VERSION 5.7 ;
BUSBITCHARS "[]" ;
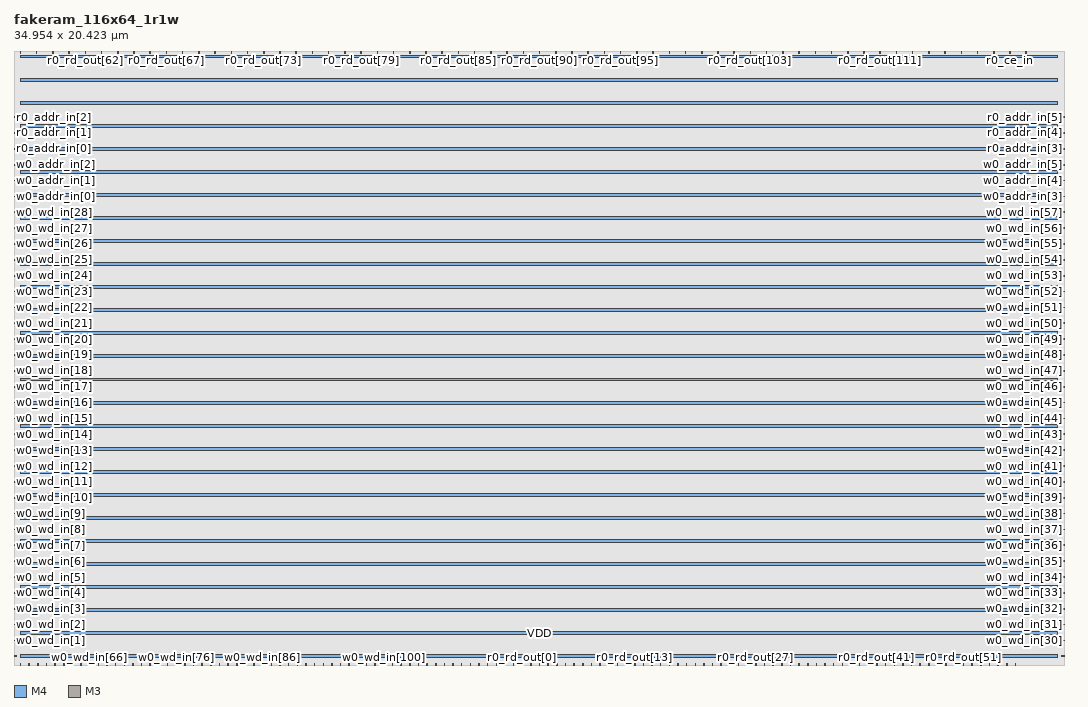
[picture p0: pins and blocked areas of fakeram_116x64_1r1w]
MACRO fakeram_116x64_1r1w
  FOREIGN fakeram_116x64_1r1w 0 0 ;
  SYMMETRY X Y R90 ;
  SIZE 34.954 BY 20.423 ;
  CLASS BLOCK ;
  PIN w0_wd_in[0]
    DIRECTION INPUT ;
    USE SIGNAL ;
    SHAPE ABUTMENT ;
    PORT
      LAYER M4 ;
      RECT 0.000 0.276 0.072 0.300 ;
    END
  END w0_wd_in[0]
  PIN w0_wd_in[1]
    DIRECTION INPUT ;
    USE SIGNAL ;
    SHAPE ABUTMENT ;
    PORT
      LAYER M4 ;
      RECT 0.000 0.804 0.072 0.828 ;
    END
  END w0_wd_in[1]
  PIN w0_wd_in[2]
    DIRECTION INPUT ;
    USE SIGNAL ;
    SHAPE ABUTMENT ;
    PORT
      LAYER M4 ;
      RECT 0.000 1.332 0.072 1.356 ;
    END
  END w0_wd_in[2]
  PIN w0_wd_in[3]
    DIRECTION INPUT ;
    USE SIGNAL ;
    SHAPE ABUTMENT ;
    PORT
      LAYER M4 ;
      RECT 0.000 1.860 0.072 1.884 ;
    END
  END w0_wd_in[3]
  PIN w0_wd_in[4]
    DIRECTION INPUT ;
    USE SIGNAL ;
    SHAPE ABUTMENT ;
    PORT
      LAYER M4 ;
      RECT 0.000 2.388 0.072 2.412 ;
    END
  END w0_wd_in[4]
  PIN w0_wd_in[5]
    DIRECTION INPUT ;
    USE SIGNAL ;
    SHAPE ABUTMENT ;
    PORT
      LAYER M4 ;
      RECT 0.000 2.916 0.072 2.940 ;
    END
  END w0_wd_in[5]
  PIN w0_wd_in[6]
    DIRECTION INPUT ;
    USE SIGNAL ;
    SHAPE ABUTMENT ;
    PORT
      LAYER M4 ;
      RECT 0.000 3.444 0.072 3.468 ;
    END
  END w0_wd_in[6]
  PIN w0_wd_in[7]
    DIRECTION INPUT ;
    USE SIGNAL ;
    SHAPE ABUTMENT ;
    PORT
      LAYER M4 ;
      RECT 0.000 3.972 0.072 3.996 ;
    END
  END w0_wd_in[7]
  PIN w0_wd_in[8]
    DIRECTION INPUT ;
    USE SIGNAL ;
    SHAPE ABUTMENT ;
    PORT
      LAYER M4 ;
      RECT 0.000 4.500 0.072 4.524 ;
    END
  END w0_wd_in[8]
  PIN w0_wd_in[9]
    DIRECTION INPUT ;
    USE SIGNAL ;
    SHAPE ABUTMENT ;
    PORT
      LAYER M4 ;
      RECT 0.000 5.028 0.072 5.052 ;
    END
  END w0_wd_in[9]
  PIN w0_wd_in[10]
    DIRECTION INPUT ;
    USE SIGNAL ;
    SHAPE ABUTMENT ;
    PORT
      LAYER M4 ;
      RECT 0.000 5.556 0.072 5.580 ;
    END
  END w0_wd_in[10]
  PIN w0_wd_in[11]
    DIRECTION INPUT ;
    USE SIGNAL ;
    SHAPE ABUTMENT ;
    PORT
      LAYER M4 ;
      RECT 0.000 6.084 0.072 6.108 ;
    END
  END w0_wd_in[11]
  PIN w0_wd_in[12]
    DIRECTION INPUT ;
    USE SIGNAL ;
    SHAPE ABUTMENT ;
    PORT
      LAYER M4 ;
      RECT 0.000 6.612 0.072 6.636 ;
    END
  END w0_wd_in[12]
  PIN w0_wd_in[13]
    DIRECTION INPUT ;
    USE SIGNAL ;
    SHAPE ABUTMENT ;
    PORT
      LAYER M4 ;
      RECT 0.000 7.140 0.072 7.164 ;
    END
  END w0_wd_in[13]
  PIN w0_wd_in[14]
    DIRECTION INPUT ;
    USE SIGNAL ;
    SHAPE ABUTMENT ;
    PORT
      LAYER M4 ;
      RECT 0.000 7.668 0.072 7.692 ;
    END
  END w0_wd_in[14]
  PIN w0_wd_in[15]
    DIRECTION INPUT ;
    USE SIGNAL ;
    SHAPE ABUTMENT ;
    PORT
      LAYER M4 ;
      RECT 0.000 8.196 0.072 8.220 ;
    END
  END w0_wd_in[15]
  PIN w0_wd_in[16]
    DIRECTION INPUT ;
    USE SIGNAL ;
    SHAPE ABUTMENT ;
    PORT
      LAYER M4 ;
      RECT 0.000 8.724 0.072 8.748 ;
    END
  END w0_wd_in[16]
  PIN w0_wd_in[17]
    DIRECTION INPUT ;
    USE SIGNAL ;
    SHAPE ABUTMENT ;
    PORT
      LAYER M4 ;
      RECT 0.000 9.252 0.072 9.276 ;
    END
  END w0_wd_in[17]
  PIN w0_wd_in[18]
    DIRECTION INPUT ;
    USE SIGNAL ;
    SHAPE ABUTMENT ;
    PORT
      LAYER M4 ;
      RECT 0.000 9.780 0.072 9.804 ;
    END
  END w0_wd_in[18]
  PIN w0_wd_in[19]
    DIRECTION INPUT ;
    USE SIGNAL ;
    SHAPE ABUTMENT ;
    PORT
      LAYER M4 ;
      RECT 0.000 10.308 0.072 10.332 ;
    END
  END w0_wd_in[19]
  PIN w0_wd_in[20]
    DIRECTION INPUT ;
    USE SIGNAL ;
    SHAPE ABUTMENT ;
    PORT
      LAYER M4 ;
      RECT 0.000 10.836 0.072 10.860 ;
    END
  END w0_wd_in[20]
  PIN w0_wd_in[21]
    DIRECTION INPUT ;
    USE SIGNAL ;
    SHAPE ABUTMENT ;
    PORT
      LAYER M4 ;
      RECT 0.000 11.364 0.072 11.388 ;
    END
  END w0_wd_in[21]
  PIN w0_wd_in[22]
    DIRECTION INPUT ;
    USE SIGNAL ;
    SHAPE ABUTMENT ;
    PORT
      LAYER M4 ;
      RECT 0.000 11.892 0.072 11.916 ;
    END
  END w0_wd_in[22]
  PIN w0_wd_in[23]
    DIRECTION INPUT ;
    USE SIGNAL ;
    SHAPE ABUTMENT ;
    PORT
      LAYER M4 ;
      RECT 0.000 12.420 0.072 12.444 ;
    END
  END w0_wd_in[23]
  PIN w0_wd_in[24]
    DIRECTION INPUT ;
    USE SIGNAL ;
    SHAPE ABUTMENT ;
    PORT
      LAYER M4 ;
      RECT 0.000 12.948 0.072 12.972 ;
    END
  END w0_wd_in[24]
  PIN w0_wd_in[25]
    DIRECTION INPUT ;
    USE SIGNAL ;
    SHAPE ABUTMENT ;
    PORT
      LAYER M4 ;
      RECT 0.000 13.476 0.072 13.500 ;
    END
  END w0_wd_in[25]
  PIN w0_wd_in[26]
    DIRECTION INPUT ;
    USE SIGNAL ;
    SHAPE ABUTMENT ;
    PORT
      LAYER M4 ;
      RECT 0.000 14.004 0.072 14.028 ;
    END
  END w0_wd_in[26]
  PIN w0_wd_in[27]
    DIRECTION INPUT ;
    USE SIGNAL ;
    SHAPE ABUTMENT ;
    PORT
      LAYER M4 ;
      RECT 0.000 14.532 0.072 14.556 ;
    END
  END w0_wd_in[27]
  PIN w0_wd_in[28]
    DIRECTION INPUT ;
    USE SIGNAL ;
    SHAPE ABUTMENT ;
    PORT
      LAYER M4 ;
      RECT 0.000 15.060 0.072 15.084 ;
    END
  END w0_wd_in[28]
  PIN w0_wd_in[29]
    DIRECTION INPUT ;
    USE SIGNAL ;
    SHAPE ABUTMENT ;
    PORT
      LAYER M4 ;
      RECT 34.882 0.276 34.954 0.300 ;
    END
  END w0_wd_in[29]
  PIN w0_wd_in[30]
    DIRECTION INPUT ;
    USE SIGNAL ;
    SHAPE ABUTMENT ;
    PORT
      LAYER M4 ;
      RECT 34.882 0.804 34.954 0.828 ;
    END
  END w0_wd_in[30]
  PIN w0_wd_in[31]
    DIRECTION INPUT ;
    USE SIGNAL ;
    SHAPE ABUTMENT ;
    PORT
      LAYER M4 ;
      RECT 34.882 1.332 34.954 1.356 ;
    END
  END w0_wd_in[31]
  PIN w0_wd_in[32]
    DIRECTION INPUT ;
    USE SIGNAL ;
    SHAPE ABUTMENT ;
    PORT
      LAYER M4 ;
      RECT 34.882 1.860 34.954 1.884 ;
    END
  END w0_wd_in[32]
  PIN w0_wd_in[33]
    DIRECTION INPUT ;
    USE SIGNAL ;
    SHAPE ABUTMENT ;
    PORT
      LAYER M4 ;
      RECT 34.882 2.388 34.954 2.412 ;
    END
  END w0_wd_in[33]
  PIN w0_wd_in[34]
    DIRECTION INPUT ;
    USE SIGNAL ;
    SHAPE ABUTMENT ;
    PORT
      LAYER M4 ;
      RECT 34.882 2.916 34.954 2.940 ;
    END
  END w0_wd_in[34]
  PIN w0_wd_in[35]
    DIRECTION INPUT ;
    USE SIGNAL ;
    SHAPE ABUTMENT ;
    PORT
      LAYER M4 ;
      RECT 34.882 3.444 34.954 3.468 ;
    END
  END w0_wd_in[35]
  PIN w0_wd_in[36]
    DIRECTION INPUT ;
    USE SIGNAL ;
    SHAPE ABUTMENT ;
    PORT
      LAYER M4 ;
      RECT 34.882 3.972 34.954 3.996 ;
    END
  END w0_wd_in[36]
  PIN w0_wd_in[37]
    DIRECTION INPUT ;
    USE SIGNAL ;
    SHAPE ABUTMENT ;
    PORT
      LAYER M4 ;
      RECT 34.882 4.500 34.954 4.524 ;
    END
  END w0_wd_in[37]
  PIN w0_wd_in[38]
    DIRECTION INPUT ;
    USE SIGNAL ;
    SHAPE ABUTMENT ;
    PORT
      LAYER M4 ;
      RECT 34.882 5.028 34.954 5.052 ;
    END
  END w0_wd_in[38]
  PIN w0_wd_in[39]
    DIRECTION INPUT ;
    USE SIGNAL ;
    SHAPE ABUTMENT ;
    PORT
      LAYER M4 ;
      RECT 34.882 5.556 34.954 5.580 ;
    END
  END w0_wd_in[39]
  PIN w0_wd_in[40]
    DIRECTION INPUT ;
    USE SIGNAL ;
    SHAPE ABUTMENT ;
    PORT
      LAYER M4 ;
      RECT 34.882 6.084 34.954 6.108 ;
    END
  END w0_wd_in[40]
  PIN w0_wd_in[41]
    DIRECTION INPUT ;
    USE SIGNAL ;
    SHAPE ABUTMENT ;
    PORT
      LAYER M4 ;
      RECT 34.882 6.612 34.954 6.636 ;
    END
  END w0_wd_in[41]
  PIN w0_wd_in[42]
    DIRECTION INPUT ;
    USE SIGNAL ;
    SHAPE ABUTMENT ;
    PORT
      LAYER M4 ;
      RECT 34.882 7.140 34.954 7.164 ;
    END
  END w0_wd_in[42]
  PIN w0_wd_in[43]
    DIRECTION INPUT ;
    USE SIGNAL ;
    SHAPE ABUTMENT ;
    PORT
      LAYER M4 ;
      RECT 34.882 7.668 34.954 7.692 ;
    END
  END w0_wd_in[43]
  PIN w0_wd_in[44]
    DIRECTION INPUT ;
    USE SIGNAL ;
    SHAPE ABUTMENT ;
    PORT
      LAYER M4 ;
      RECT 34.882 8.196 34.954 8.220 ;
    END
  END w0_wd_in[44]
  PIN w0_wd_in[45]
    DIRECTION INPUT ;
    USE SIGNAL ;
    SHAPE ABUTMENT ;
    PORT
      LAYER M4 ;
      RECT 34.882 8.724 34.954 8.748 ;
    END
  END w0_wd_in[45]
  PIN w0_wd_in[46]
    DIRECTION INPUT ;
    USE SIGNAL ;
    SHAPE ABUTMENT ;
    PORT
      LAYER M4 ;
      RECT 34.882 9.252 34.954 9.276 ;
    END
  END w0_wd_in[46]
  PIN w0_wd_in[47]
    DIRECTION INPUT ;
    USE SIGNAL ;
    SHAPE ABUTMENT ;
    PORT
      LAYER M4 ;
      RECT 34.882 9.780 34.954 9.804 ;
    END
  END w0_wd_in[47]
  PIN w0_wd_in[48]
    DIRECTION INPUT ;
    USE SIGNAL ;
    SHAPE ABUTMENT ;
    PORT
      LAYER M4 ;
      RECT 34.882 10.308 34.954 10.332 ;
    END
  END w0_wd_in[48]
  PIN w0_wd_in[49]
    DIRECTION INPUT ;
    USE SIGNAL ;
    SHAPE ABUTMENT ;
    PORT
      LAYER M4 ;
      RECT 34.882 10.836 34.954 10.860 ;
    END
  END w0_wd_in[49]
  PIN w0_wd_in[50]
    DIRECTION INPUT ;
    USE SIGNAL ;
    SHAPE ABUTMENT ;
    PORT
      LAYER M4 ;
      RECT 34.882 11.364 34.954 11.388 ;
    END
  END w0_wd_in[50]
  PIN w0_wd_in[51]
    DIRECTION INPUT ;
    USE SIGNAL ;
    SHAPE ABUTMENT ;
    PORT
      LAYER M4 ;
      RECT 34.882 11.892 34.954 11.916 ;
    END
  END w0_wd_in[51]
  PIN w0_wd_in[52]
    DIRECTION INPUT ;
    USE SIGNAL ;
    SHAPE ABUTMENT ;
    PORT
      LAYER M4 ;
      RECT 34.882 12.420 34.954 12.444 ;
    END
  END w0_wd_in[52]
  PIN w0_wd_in[53]
    DIRECTION INPUT ;
    USE SIGNAL ;
    SHAPE ABUTMENT ;
    PORT
      LAYER M4 ;
      RECT 34.882 12.948 34.954 12.972 ;
    END
  END w0_wd_in[53]
  PIN w0_wd_in[54]
    DIRECTION INPUT ;
    USE SIGNAL ;
    SHAPE ABUTMENT ;
    PORT
      LAYER M4 ;
      RECT 34.882 13.476 34.954 13.500 ;
    END
  END w0_wd_in[54]
  PIN w0_wd_in[55]
    DIRECTION INPUT ;
    USE SIGNAL ;
    SHAPE ABUTMENT ;
    PORT
      LAYER M4 ;
      RECT 34.882 14.004 34.954 14.028 ;
    END
  END w0_wd_in[55]
  PIN w0_wd_in[56]
    DIRECTION INPUT ;
    USE SIGNAL ;
    SHAPE ABUTMENT ;
    PORT
      LAYER M4 ;
      RECT 34.882 14.532 34.954 14.556 ;
    END
  END w0_wd_in[56]
  PIN w0_wd_in[57]
    DIRECTION INPUT ;
    USE SIGNAL ;
    SHAPE ABUTMENT ;
    PORT
      LAYER M4 ;
      RECT 34.882 15.060 34.954 15.084 ;
    END
  END w0_wd_in[57]
  PIN w0_wd_in[58]
    DIRECTION OUTPUT ;
    USE SIGNAL ;
    SHAPE ABUTMENT ;
    PORT
      LAYER M3 ;
      RECT 0.207 0.000 0.225 0.054 ;
    END
  END w0_wd_in[58]
  PIN w0_wd_in[59]
    DIRECTION OUTPUT ;
    USE SIGNAL ;
    SHAPE ABUTMENT ;
    PORT
      LAYER M3 ;
      RECT 0.495 0.000 0.513 0.054 ;
    END
  END w0_wd_in[59]
  PIN w0_wd_in[60]
    DIRECTION OUTPUT ;
    USE SIGNAL ;
    SHAPE ABUTMENT ;
    PORT
      LAYER M3 ;
      RECT 0.783 0.000 0.801 0.054 ;
    END
  END w0_wd_in[60]
  PIN w0_wd_in[61]
    DIRECTION OUTPUT ;
    USE SIGNAL ;
    SHAPE ABUTMENT ;
    PORT
      LAYER M3 ;
      RECT 1.071 0.000 1.089 0.054 ;
    END
  END w0_wd_in[61]
  PIN w0_wd_in[62]
    DIRECTION OUTPUT ;
    USE SIGNAL ;
    SHAPE ABUTMENT ;
    PORT
      LAYER M3 ;
      RECT 1.359 0.000 1.377 0.054 ;
    END
  END w0_wd_in[62]
  PIN w0_wd_in[63]
    DIRECTION OUTPUT ;
    USE SIGNAL ;
    SHAPE ABUTMENT ;
    PORT
      LAYER M3 ;
      RECT 1.647 0.000 1.665 0.054 ;
    END
  END w0_wd_in[63]
  PIN w0_wd_in[64]
    DIRECTION OUTPUT ;
    USE SIGNAL ;
    SHAPE ABUTMENT ;
    PORT
      LAYER M3 ;
      RECT 1.935 0.000 1.953 0.054 ;
    END
  END w0_wd_in[64]
  PIN w0_wd_in[65]
    DIRECTION OUTPUT ;
    USE SIGNAL ;
    SHAPE ABUTMENT ;
    PORT
      LAYER M3 ;
      RECT 2.223 0.000 2.241 0.054 ;
    END
  END w0_wd_in[65]
  PIN w0_wd_in[66]
    DIRECTION OUTPUT ;
    USE SIGNAL ;
    SHAPE ABUTMENT ;
    PORT
      LAYER M3 ;
      RECT 2.511 0.000 2.529 0.054 ;
    END
  END w0_wd_in[66]
  PIN w0_wd_in[67]
    DIRECTION OUTPUT ;
    USE SIGNAL ;
    SHAPE ABUTMENT ;
    PORT
      LAYER M3 ;
      RECT 2.799 0.000 2.817 0.054 ;
    END
  END w0_wd_in[67]
  PIN w0_wd_in[68]
    DIRECTION OUTPUT ;
    USE SIGNAL ;
    SHAPE ABUTMENT ;
    PORT
      LAYER M3 ;
      RECT 3.087 0.000 3.105 0.054 ;
    END
  END w0_wd_in[68]
  PIN w0_wd_in[69]
    DIRECTION OUTPUT ;
    USE SIGNAL ;
    SHAPE ABUTMENT ;
    PORT
      LAYER M3 ;
      RECT 3.375 0.000 3.393 0.054 ;
    END
  END w0_wd_in[69]
  PIN w0_wd_in[70]
    DIRECTION OUTPUT ;
    USE SIGNAL ;
    SHAPE ABUTMENT ;
    PORT
      LAYER M3 ;
      RECT 3.663 0.000 3.681 0.054 ;
    END
  END w0_wd_in[70]
  PIN w0_wd_in[71]
    DIRECTION OUTPUT ;
    USE SIGNAL ;
    SHAPE ABUTMENT ;
    PORT
      LAYER M3 ;
      RECT 3.951 0.000 3.969 0.054 ;
    END
  END w0_wd_in[71]
  PIN w0_wd_in[72]
    DIRECTION OUTPUT ;
    USE SIGNAL ;
    SHAPE ABUTMENT ;
    PORT
      LAYER M3 ;
      RECT 4.239 0.000 4.257 0.054 ;
    END
  END w0_wd_in[72]
  PIN w0_wd_in[73]
    DIRECTION OUTPUT ;
    USE SIGNAL ;
    SHAPE ABUTMENT ;
    PORT
      LAYER M3 ;
      RECT 4.527 0.000 4.545 0.054 ;
    END
  END w0_wd_in[73]
  PIN w0_wd_in[74]
    DIRECTION OUTPUT ;
    USE SIGNAL ;
    SHAPE ABUTMENT ;
    PORT
      LAYER M3 ;
      RECT 4.815 0.000 4.833 0.054 ;
    END
  END w0_wd_in[74]
  PIN w0_wd_in[75]
    DIRECTION OUTPUT ;
    USE SIGNAL ;
    SHAPE ABUTMENT ;
    PORT
      LAYER M3 ;
      RECT 5.103 0.000 5.121 0.054 ;
    END
  END w0_wd_in[75]
  PIN w0_wd_in[76]
    DIRECTION OUTPUT ;
    USE SIGNAL ;
    SHAPE ABUTMENT ;
    PORT
      LAYER M3 ;
      RECT 5.391 0.000 5.409 0.054 ;
    END
  END w0_wd_in[76]
  PIN w0_wd_in[77]
    DIRECTION OUTPUT ;
    USE SIGNAL ;
    SHAPE ABUTMENT ;
    PORT
      LAYER M3 ;
      RECT 5.679 0.000 5.697 0.054 ;
    END
  END w0_wd_in[77]
  PIN w0_wd_in[78]
    DIRECTION OUTPUT ;
    USE SIGNAL ;
    SHAPE ABUTMENT ;
    PORT
      LAYER M3 ;
      RECT 5.967 0.000 5.985 0.054 ;
    END
  END w0_wd_in[78]
  PIN w0_wd_in[79]
    DIRECTION OUTPUT ;
    USE SIGNAL ;
    SHAPE ABUTMENT ;
    PORT
      LAYER M3 ;
      RECT 6.255 0.000 6.273 0.054 ;
    END
  END w0_wd_in[79]
  PIN w0_wd_in[80]
    DIRECTION OUTPUT ;
    USE SIGNAL ;
    SHAPE ABUTMENT ;
    PORT
      LAYER M3 ;
      RECT 6.543 0.000 6.561 0.054 ;
    END
  END w0_wd_in[80]
  PIN w0_wd_in[81]
    DIRECTION OUTPUT ;
    USE SIGNAL ;
    SHAPE ABUTMENT ;
    PORT
      LAYER M3 ;
      RECT 6.831 0.000 6.849 0.054 ;
    END
  END w0_wd_in[81]
  PIN w0_wd_in[82]
    DIRECTION OUTPUT ;
    USE SIGNAL ;
    SHAPE ABUTMENT ;
    PORT
      LAYER M3 ;
      RECT 7.119 0.000 7.137 0.054 ;
    END
  END w0_wd_in[82]
  PIN w0_wd_in[83]
    DIRECTION OUTPUT ;
    USE SIGNAL ;
    SHAPE ABUTMENT ;
    PORT
      LAYER M3 ;
      RECT 7.407 0.000 7.425 0.054 ;
    END
  END w0_wd_in[83]
  PIN w0_wd_in[84]
    DIRECTION OUTPUT ;
    USE SIGNAL ;
    SHAPE ABUTMENT ;
    PORT
      LAYER M3 ;
      RECT 7.695 0.000 7.713 0.054 ;
    END
  END w0_wd_in[84]
  PIN w0_wd_in[85]
    DIRECTION OUTPUT ;
    USE SIGNAL ;
    SHAPE ABUTMENT ;
    PORT
      LAYER M3 ;
      RECT 7.983 0.000 8.001 0.054 ;
    END
  END w0_wd_in[85]
  PIN w0_wd_in[86]
    DIRECTION OUTPUT ;
    USE SIGNAL ;
    SHAPE ABUTMENT ;
    PORT
      LAYER M3 ;
      RECT 8.271 0.000 8.289 0.054 ;
    END
  END w0_wd_in[86]
  PIN w0_wd_in[87]
    DIRECTION OUTPUT ;
    USE SIGNAL ;
    SHAPE ABUTMENT ;
    PORT
      LAYER M3 ;
      RECT 8.559 0.000 8.577 0.054 ;
    END
  END w0_wd_in[87]
  PIN w0_wd_in[88]
    DIRECTION OUTPUT ;
    USE SIGNAL ;
    SHAPE ABUTMENT ;
    PORT
      LAYER M3 ;
      RECT 8.847 0.000 8.865 0.054 ;
    END
  END w0_wd_in[88]
  PIN w0_wd_in[89]
    DIRECTION OUTPUT ;
    USE SIGNAL ;
    SHAPE ABUTMENT ;
    PORT
      LAYER M3 ;
      RECT 9.135 0.000 9.153 0.054 ;
    END
  END w0_wd_in[89]
  PIN w0_wd_in[90]
    DIRECTION OUTPUT ;
    USE SIGNAL ;
    SHAPE ABUTMENT ;
    PORT
      LAYER M3 ;
      RECT 9.423 0.000 9.441 0.054 ;
    END
  END w0_wd_in[90]
  PIN w0_wd_in[91]
    DIRECTION OUTPUT ;
    USE SIGNAL ;
    SHAPE ABUTMENT ;
    PORT
      LAYER M3 ;
      RECT 9.711 0.000 9.729 0.054 ;
    END
  END w0_wd_in[91]
  PIN w0_wd_in[92]
    DIRECTION OUTPUT ;
    USE SIGNAL ;
    SHAPE ABUTMENT ;
    PORT
      LAYER M3 ;
      RECT 9.999 0.000 10.017 0.054 ;
    END
  END w0_wd_in[92]
  PIN w0_wd_in[93]
    DIRECTION OUTPUT ;
    USE SIGNAL ;
    SHAPE ABUTMENT ;
    PORT
      LAYER M3 ;
      RECT 10.287 0.000 10.305 0.054 ;
    END
  END w0_wd_in[93]
  PIN w0_wd_in[94]
    DIRECTION OUTPUT ;
    USE SIGNAL ;
    SHAPE ABUTMENT ;
    PORT
      LAYER M3 ;
      RECT 10.575 0.000 10.593 0.054 ;
    END
  END w0_wd_in[94]
  PIN w0_wd_in[95]
    DIRECTION OUTPUT ;
    USE SIGNAL ;
    SHAPE ABUTMENT ;
    PORT
      LAYER M3 ;
      RECT 10.863 0.000 10.881 0.054 ;
    END
  END w0_wd_in[95]
  PIN w0_wd_in[96]
    DIRECTION OUTPUT ;
    USE SIGNAL ;
    SHAPE ABUTMENT ;
    PORT
      LAYER M3 ;
      RECT 11.151 0.000 11.169 0.054 ;
    END
  END w0_wd_in[96]
  PIN w0_wd_in[97]
    DIRECTION OUTPUT ;
    USE SIGNAL ;
    SHAPE ABUTMENT ;
    PORT
      LAYER M3 ;
      RECT 11.439 0.000 11.457 0.054 ;
    END
  END w0_wd_in[97]
  PIN w0_wd_in[98]
    DIRECTION OUTPUT ;
    USE SIGNAL ;
    SHAPE ABUTMENT ;
    PORT
      LAYER M3 ;
      RECT 11.727 0.000 11.745 0.054 ;
    END
  END w0_wd_in[98]
  PIN w0_wd_in[99]
    DIRECTION OUTPUT ;
    USE SIGNAL ;
    SHAPE ABUTMENT ;
    PORT
      LAYER M3 ;
      RECT 12.015 0.000 12.033 0.054 ;
    END
  END w0_wd_in[99]
  PIN w0_wd_in[100]
    DIRECTION OUTPUT ;
    USE SIGNAL ;
    SHAPE ABUTMENT ;
    PORT
      LAYER M3 ;
      RECT 12.303 0.000 12.321 0.054 ;
    END
  END w0_wd_in[100]
  PIN w0_wd_in[101]
    DIRECTION OUTPUT ;
    USE SIGNAL ;
    SHAPE ABUTMENT ;
    PORT
      LAYER M3 ;
      RECT 12.591 0.000 12.609 0.054 ;
    END
  END w0_wd_in[101]
  PIN w0_wd_in[102]
    DIRECTION OUTPUT ;
    USE SIGNAL ;
    SHAPE ABUTMENT ;
    PORT
      LAYER M3 ;
      RECT 12.879 0.000 12.897 0.054 ;
    END
  END w0_wd_in[102]
  PIN w0_wd_in[103]
    DIRECTION OUTPUT ;
    USE SIGNAL ;
    SHAPE ABUTMENT ;
    PORT
      LAYER M3 ;
      RECT 13.167 0.000 13.185 0.054 ;
    END
  END w0_wd_in[103]
  PIN w0_wd_in[104]
    DIRECTION OUTPUT ;
    USE SIGNAL ;
    SHAPE ABUTMENT ;
    PORT
      LAYER M3 ;
      RECT 13.455 0.000 13.473 0.054 ;
    END
  END w0_wd_in[104]
  PIN w0_wd_in[105]
    DIRECTION OUTPUT ;
    USE SIGNAL ;
    SHAPE ABUTMENT ;
    PORT
      LAYER M3 ;
      RECT 13.743 0.000 13.761 0.054 ;
    END
  END w0_wd_in[105]
  PIN w0_wd_in[106]
    DIRECTION OUTPUT ;
    USE SIGNAL ;
    SHAPE ABUTMENT ;
    PORT
      LAYER M3 ;
      RECT 14.031 0.000 14.049 0.054 ;
    END
  END w0_wd_in[106]
  PIN w0_wd_in[107]
    DIRECTION OUTPUT ;
    USE SIGNAL ;
    SHAPE ABUTMENT ;
    PORT
      LAYER M3 ;
      RECT 14.319 0.000 14.337 0.054 ;
    END
  END w0_wd_in[107]
  PIN w0_wd_in[108]
    DIRECTION OUTPUT ;
    USE SIGNAL ;
    SHAPE ABUTMENT ;
    PORT
      LAYER M3 ;
      RECT 14.607 0.000 14.625 0.054 ;
    END
  END w0_wd_in[108]
  PIN w0_wd_in[109]
    DIRECTION OUTPUT ;
    USE SIGNAL ;
    SHAPE ABUTMENT ;
    PORT
      LAYER M3 ;
      RECT 14.895 0.000 14.913 0.054 ;
    END
  END w0_wd_in[109]
  PIN w0_wd_in[110]
    DIRECTION OUTPUT ;
    USE SIGNAL ;
    SHAPE ABUTMENT ;
    PORT
      LAYER M3 ;
      RECT 15.183 0.000 15.201 0.054 ;
    END
  END w0_wd_in[110]
  PIN w0_wd_in[111]
    DIRECTION OUTPUT ;
    USE SIGNAL ;
    SHAPE ABUTMENT ;
    PORT
      LAYER M3 ;
      RECT 15.471 0.000 15.489 0.054 ;
    END
  END w0_wd_in[111]
  PIN w0_wd_in[112]
    DIRECTION OUTPUT ;
    USE SIGNAL ;
    SHAPE ABUTMENT ;
    PORT
      LAYER M3 ;
      RECT 15.759 0.000 15.777 0.054 ;
    END
  END w0_wd_in[112]
  PIN w0_wd_in[113]
    DIRECTION OUTPUT ;
    USE SIGNAL ;
    SHAPE ABUTMENT ;
    PORT
      LAYER M3 ;
      RECT 16.047 0.000 16.065 0.054 ;
    END
  END w0_wd_in[113]
  PIN w0_wd_in[114]
    DIRECTION OUTPUT ;
    USE SIGNAL ;
    SHAPE ABUTMENT ;
    PORT
      LAYER M3 ;
      RECT 16.335 0.000 16.353 0.054 ;
    END
  END w0_wd_in[114]
  PIN w0_wd_in[115]
    DIRECTION OUTPUT ;
    USE SIGNAL ;
    SHAPE ABUTMENT ;
    PORT
      LAYER M3 ;
      RECT 16.623 0.000 16.641 0.054 ;
    END
  END w0_wd_in[115]
  PIN r0_rd_out[0]
    DIRECTION OUTPUT ;
    USE SIGNAL ;
    SHAPE ABUTMENT ;
    PORT
      LAYER M3 ;
      RECT 16.911 0.000 16.929 0.054 ;
    END
  END r0_rd_out[0]
  PIN r0_rd_out[1]
    DIRECTION OUTPUT ;
    USE SIGNAL ;
    SHAPE ABUTMENT ;
    PORT
      LAYER M3 ;
      RECT 17.199 0.000 17.217 0.054 ;
    END
  END r0_rd_out[1]
  PIN r0_rd_out[2]
    DIRECTION OUTPUT ;
    USE SIGNAL ;
    SHAPE ABUTMENT ;
    PORT
      LAYER M3 ;
      RECT 17.487 0.000 17.505 0.054 ;
    END
  END r0_rd_out[2]
  PIN r0_rd_out[3]
    DIRECTION OUTPUT ;
    USE SIGNAL ;
    SHAPE ABUTMENT ;
    PORT
      LAYER M3 ;
      RECT 17.775 0.000 17.793 0.054 ;
    END
  END r0_rd_out[3]
  PIN r0_rd_out[4]
    DIRECTION OUTPUT ;
    USE SIGNAL ;
    SHAPE ABUTMENT ;
    PORT
      LAYER M3 ;
      RECT 18.063 0.000 18.081 0.054 ;
    END
  END r0_rd_out[4]
  PIN r0_rd_out[5]
    DIRECTION OUTPUT ;
    USE SIGNAL ;
    SHAPE ABUTMENT ;
    PORT
      LAYER M3 ;
      RECT 18.351 0.000 18.369 0.054 ;
    END
  END r0_rd_out[5]
  PIN r0_rd_out[6]
    DIRECTION OUTPUT ;
    USE SIGNAL ;
    SHAPE ABUTMENT ;
    PORT
      LAYER M3 ;
      RECT 18.639 0.000 18.657 0.054 ;
    END
  END r0_rd_out[6]
  PIN r0_rd_out[7]
    DIRECTION OUTPUT ;
    USE SIGNAL ;
    SHAPE ABUTMENT ;
    PORT
      LAYER M3 ;
      RECT 18.927 0.000 18.945 0.054 ;
    END
  END r0_rd_out[7]
  PIN r0_rd_out[8]
    DIRECTION OUTPUT ;
    USE SIGNAL ;
    SHAPE ABUTMENT ;
    PORT
      LAYER M3 ;
      RECT 19.215 0.000 19.233 0.054 ;
    END
  END r0_rd_out[8]
  PIN r0_rd_out[9]
    DIRECTION OUTPUT ;
    USE SIGNAL ;
    SHAPE ABUTMENT ;
    PORT
      LAYER M3 ;
      RECT 19.503 0.000 19.521 0.054 ;
    END
  END r0_rd_out[9]
  PIN r0_rd_out[10]
    DIRECTION OUTPUT ;
    USE SIGNAL ;
    SHAPE ABUTMENT ;
    PORT
      LAYER M3 ;
      RECT 19.791 0.000 19.809 0.054 ;
    END
  END r0_rd_out[10]
  PIN r0_rd_out[11]
    DIRECTION OUTPUT ;
    USE SIGNAL ;
    SHAPE ABUTMENT ;
    PORT
      LAYER M3 ;
      RECT 20.079 0.000 20.097 0.054 ;
    END
  END r0_rd_out[11]
  PIN r0_rd_out[12]
    DIRECTION OUTPUT ;
    USE SIGNAL ;
    SHAPE ABUTMENT ;
    PORT
      LAYER M3 ;
      RECT 20.367 0.000 20.385 0.054 ;
    END
  END r0_rd_out[12]
  PIN r0_rd_out[13]
    DIRECTION OUTPUT ;
    USE SIGNAL ;
    SHAPE ABUTMENT ;
    PORT
      LAYER M3 ;
      RECT 20.655 0.000 20.673 0.054 ;
    END
  END r0_rd_out[13]
  PIN r0_rd_out[14]
    DIRECTION OUTPUT ;
    USE SIGNAL ;
    SHAPE ABUTMENT ;
    PORT
      LAYER M3 ;
      RECT 20.943 0.000 20.961 0.054 ;
    END
  END r0_rd_out[14]
  PIN r0_rd_out[15]
    DIRECTION OUTPUT ;
    USE SIGNAL ;
    SHAPE ABUTMENT ;
    PORT
      LAYER M3 ;
      RECT 21.231 0.000 21.249 0.054 ;
    END
  END r0_rd_out[15]
  PIN r0_rd_out[16]
    DIRECTION OUTPUT ;
    USE SIGNAL ;
    SHAPE ABUTMENT ;
    PORT
      LAYER M3 ;
      RECT 21.519 0.000 21.537 0.054 ;
    END
  END r0_rd_out[16]
  PIN r0_rd_out[17]
    DIRECTION OUTPUT ;
    USE SIGNAL ;
    SHAPE ABUTMENT ;
    PORT
      LAYER M3 ;
      RECT 21.807 0.000 21.825 0.054 ;
    END
  END r0_rd_out[17]
  PIN r0_rd_out[18]
    DIRECTION OUTPUT ;
    USE SIGNAL ;
    SHAPE ABUTMENT ;
    PORT
      LAYER M3 ;
      RECT 22.095 0.000 22.113 0.054 ;
    END
  END r0_rd_out[18]
  PIN r0_rd_out[19]
    DIRECTION OUTPUT ;
    USE SIGNAL ;
    SHAPE ABUTMENT ;
    PORT
      LAYER M3 ;
      RECT 22.383 0.000 22.401 0.054 ;
    END
  END r0_rd_out[19]
  PIN r0_rd_out[20]
    DIRECTION OUTPUT ;
    USE SIGNAL ;
    SHAPE ABUTMENT ;
    PORT
      LAYER M3 ;
      RECT 22.671 0.000 22.689 0.054 ;
    END
  END r0_rd_out[20]
  PIN r0_rd_out[21]
    DIRECTION OUTPUT ;
    USE SIGNAL ;
    SHAPE ABUTMENT ;
    PORT
      LAYER M3 ;
      RECT 22.959 0.000 22.977 0.054 ;
    END
  END r0_rd_out[21]
  PIN r0_rd_out[22]
    DIRECTION OUTPUT ;
    USE SIGNAL ;
    SHAPE ABUTMENT ;
    PORT
      LAYER M3 ;
      RECT 23.247 0.000 23.265 0.054 ;
    END
  END r0_rd_out[22]
  PIN r0_rd_out[23]
    DIRECTION OUTPUT ;
    USE SIGNAL ;
    SHAPE ABUTMENT ;
    PORT
      LAYER M3 ;
      RECT 23.535 0.000 23.553 0.054 ;
    END
  END r0_rd_out[23]
  PIN r0_rd_out[24]
    DIRECTION OUTPUT ;
    USE SIGNAL ;
    SHAPE ABUTMENT ;
    PORT
      LAYER M3 ;
      RECT 23.823 0.000 23.841 0.054 ;
    END
  END r0_rd_out[24]
  PIN r0_rd_out[25]
    DIRECTION OUTPUT ;
    USE SIGNAL ;
    SHAPE ABUTMENT ;
    PORT
      LAYER M3 ;
      RECT 24.111 0.000 24.129 0.054 ;
    END
  END r0_rd_out[25]
  PIN r0_rd_out[26]
    DIRECTION OUTPUT ;
    USE SIGNAL ;
    SHAPE ABUTMENT ;
    PORT
      LAYER M3 ;
      RECT 24.399 0.000 24.417 0.054 ;
    END
  END r0_rd_out[26]
  PIN r0_rd_out[27]
    DIRECTION OUTPUT ;
    USE SIGNAL ;
    SHAPE ABUTMENT ;
    PORT
      LAYER M3 ;
      RECT 24.687 0.000 24.705 0.054 ;
    END
  END r0_rd_out[27]
  PIN r0_rd_out[28]
    DIRECTION OUTPUT ;
    USE SIGNAL ;
    SHAPE ABUTMENT ;
    PORT
      LAYER M3 ;
      RECT 24.975 0.000 24.993 0.054 ;
    END
  END r0_rd_out[28]
  PIN r0_rd_out[29]
    DIRECTION OUTPUT ;
    USE SIGNAL ;
    SHAPE ABUTMENT ;
    PORT
      LAYER M3 ;
      RECT 25.263 0.000 25.281 0.054 ;
    END
  END r0_rd_out[29]
  PIN r0_rd_out[30]
    DIRECTION OUTPUT ;
    USE SIGNAL ;
    SHAPE ABUTMENT ;
    PORT
      LAYER M3 ;
      RECT 25.551 0.000 25.569 0.054 ;
    END
  END r0_rd_out[30]
  PIN r0_rd_out[31]
    DIRECTION OUTPUT ;
    USE SIGNAL ;
    SHAPE ABUTMENT ;
    PORT
      LAYER M3 ;
      RECT 25.839 0.000 25.857 0.054 ;
    END
  END r0_rd_out[31]
  PIN r0_rd_out[32]
    DIRECTION OUTPUT ;
    USE SIGNAL ;
    SHAPE ABUTMENT ;
    PORT
      LAYER M3 ;
      RECT 26.127 0.000 26.145 0.054 ;
    END
  END r0_rd_out[32]
  PIN r0_rd_out[33]
    DIRECTION OUTPUT ;
    USE SIGNAL ;
    SHAPE ABUTMENT ;
    PORT
      LAYER M3 ;
      RECT 26.415 0.000 26.433 0.054 ;
    END
  END r0_rd_out[33]
  PIN r0_rd_out[34]
    DIRECTION OUTPUT ;
    USE SIGNAL ;
    SHAPE ABUTMENT ;
    PORT
      LAYER M3 ;
      RECT 26.703 0.000 26.721 0.054 ;
    END
  END r0_rd_out[34]
  PIN r0_rd_out[35]
    DIRECTION OUTPUT ;
    USE SIGNAL ;
    SHAPE ABUTMENT ;
    PORT
      LAYER M3 ;
      RECT 26.991 0.000 27.009 0.054 ;
    END
  END r0_rd_out[35]
  PIN r0_rd_out[36]
    DIRECTION OUTPUT ;
    USE SIGNAL ;
    SHAPE ABUTMENT ;
    PORT
      LAYER M3 ;
      RECT 27.279 0.000 27.297 0.054 ;
    END
  END r0_rd_out[36]
  PIN r0_rd_out[37]
    DIRECTION OUTPUT ;
    USE SIGNAL ;
    SHAPE ABUTMENT ;
    PORT
      LAYER M3 ;
      RECT 27.567 0.000 27.585 0.054 ;
    END
  END r0_rd_out[37]
  PIN r0_rd_out[38]
    DIRECTION OUTPUT ;
    USE SIGNAL ;
    SHAPE ABUTMENT ;
    PORT
      LAYER M3 ;
      RECT 27.855 0.000 27.873 0.054 ;
    END
  END r0_rd_out[38]
  PIN r0_rd_out[39]
    DIRECTION OUTPUT ;
    USE SIGNAL ;
    SHAPE ABUTMENT ;
    PORT
      LAYER M3 ;
      RECT 28.143 0.000 28.161 0.054 ;
    END
  END r0_rd_out[39]
  PIN r0_rd_out[40]
    DIRECTION OUTPUT ;
    USE SIGNAL ;
    SHAPE ABUTMENT ;
    PORT
      LAYER M3 ;
      RECT 28.431 0.000 28.449 0.054 ;
    END
  END r0_rd_out[40]
  PIN r0_rd_out[41]
    DIRECTION OUTPUT ;
    USE SIGNAL ;
    SHAPE ABUTMENT ;
    PORT
      LAYER M3 ;
      RECT 28.719 0.000 28.737 0.054 ;
    END
  END r0_rd_out[41]
  PIN r0_rd_out[42]
    DIRECTION OUTPUT ;
    USE SIGNAL ;
    SHAPE ABUTMENT ;
    PORT
      LAYER M3 ;
      RECT 29.007 0.000 29.025 0.054 ;
    END
  END r0_rd_out[42]
  PIN r0_rd_out[43]
    DIRECTION OUTPUT ;
    USE SIGNAL ;
    SHAPE ABUTMENT ;
    PORT
      LAYER M3 ;
      RECT 29.295 0.000 29.313 0.054 ;
    END
  END r0_rd_out[43]
  PIN r0_rd_out[44]
    DIRECTION OUTPUT ;
    USE SIGNAL ;
    SHAPE ABUTMENT ;
    PORT
      LAYER M3 ;
      RECT 29.583 0.000 29.601 0.054 ;
    END
  END r0_rd_out[44]
  PIN r0_rd_out[45]
    DIRECTION OUTPUT ;
    USE SIGNAL ;
    SHAPE ABUTMENT ;
    PORT
      LAYER M3 ;
      RECT 29.871 0.000 29.889 0.054 ;
    END
  END r0_rd_out[45]
  PIN r0_rd_out[46]
    DIRECTION OUTPUT ;
    USE SIGNAL ;
    SHAPE ABUTMENT ;
    PORT
      LAYER M3 ;
      RECT 30.159 0.000 30.177 0.054 ;
    END
  END r0_rd_out[46]
  PIN r0_rd_out[47]
    DIRECTION OUTPUT ;
    USE SIGNAL ;
    SHAPE ABUTMENT ;
    PORT
      LAYER M3 ;
      RECT 30.447 0.000 30.465 0.054 ;
    END
  END r0_rd_out[47]
  PIN r0_rd_out[48]
    DIRECTION OUTPUT ;
    USE SIGNAL ;
    SHAPE ABUTMENT ;
    PORT
      LAYER M3 ;
      RECT 30.735 0.000 30.753 0.054 ;
    END
  END r0_rd_out[48]
  PIN r0_rd_out[49]
    DIRECTION OUTPUT ;
    USE SIGNAL ;
    SHAPE ABUTMENT ;
    PORT
      LAYER M3 ;
      RECT 31.023 0.000 31.041 0.054 ;
    END
  END r0_rd_out[49]
  PIN r0_rd_out[50]
    DIRECTION OUTPUT ;
    USE SIGNAL ;
    SHAPE ABUTMENT ;
    PORT
      LAYER M3 ;
      RECT 31.311 0.000 31.329 0.054 ;
    END
  END r0_rd_out[50]
  PIN r0_rd_out[51]
    DIRECTION OUTPUT ;
    USE SIGNAL ;
    SHAPE ABUTMENT ;
    PORT
      LAYER M3 ;
      RECT 31.599 0.000 31.617 0.054 ;
    END
  END r0_rd_out[51]
  PIN r0_rd_out[52]
    DIRECTION OUTPUT ;
    USE SIGNAL ;
    SHAPE ABUTMENT ;
    PORT
      LAYER M3 ;
      RECT 31.887 0.000 31.905 0.054 ;
    END
  END r0_rd_out[52]
  PIN r0_rd_out[53]
    DIRECTION OUTPUT ;
    USE SIGNAL ;
    SHAPE ABUTMENT ;
    PORT
      LAYER M3 ;
      RECT 32.175 0.000 32.193 0.054 ;
    END
  END r0_rd_out[53]
  PIN r0_rd_out[54]
    DIRECTION OUTPUT ;
    USE SIGNAL ;
    SHAPE ABUTMENT ;
    PORT
      LAYER M3 ;
      RECT 32.463 0.000 32.481 0.054 ;
    END
  END r0_rd_out[54]
  PIN r0_rd_out[55]
    DIRECTION OUTPUT ;
    USE SIGNAL ;
    SHAPE ABUTMENT ;
    PORT
      LAYER M3 ;
      RECT 32.751 0.000 32.769 0.054 ;
    END
  END r0_rd_out[55]
  PIN r0_rd_out[56]
    DIRECTION OUTPUT ;
    USE SIGNAL ;
    SHAPE ABUTMENT ;
    PORT
      LAYER M3 ;
      RECT 33.039 0.000 33.057 0.054 ;
    END
  END r0_rd_out[56]
  PIN r0_rd_out[57]
    DIRECTION OUTPUT ;
    USE SIGNAL ;
    SHAPE ABUTMENT ;
    PORT
      LAYER M3 ;
      RECT 33.327 0.000 33.345 0.054 ;
    END
  END r0_rd_out[57]
  PIN r0_rd_out[58]
    DIRECTION OUTPUT ;
    USE SIGNAL ;
    SHAPE ABUTMENT ;
    PORT
      LAYER M3 ;
      RECT 0.207 20.369 0.225 20.423 ;
    END
  END r0_rd_out[58]
  PIN r0_rd_out[59]
    DIRECTION OUTPUT ;
    USE SIGNAL ;
    SHAPE ABUTMENT ;
    PORT
      LAYER M3 ;
      RECT 0.747 20.369 0.765 20.423 ;
    END
  END r0_rd_out[59]
  PIN r0_rd_out[60]
    DIRECTION OUTPUT ;
    USE SIGNAL ;
    SHAPE ABUTMENT ;
    PORT
      LAYER M3 ;
      RECT 1.287 20.369 1.305 20.423 ;
    END
  END r0_rd_out[60]
  PIN r0_rd_out[61]
    DIRECTION OUTPUT ;
    USE SIGNAL ;
    SHAPE ABUTMENT ;
    PORT
      LAYER M3 ;
      RECT 1.827 20.369 1.845 20.423 ;
    END
  END r0_rd_out[61]
  PIN r0_rd_out[62]
    DIRECTION OUTPUT ;
    USE SIGNAL ;
    SHAPE ABUTMENT ;
    PORT
      LAYER M3 ;
      RECT 2.367 20.369 2.385 20.423 ;
    END
  END r0_rd_out[62]
  PIN r0_rd_out[63]
    DIRECTION OUTPUT ;
    USE SIGNAL ;
    SHAPE ABUTMENT ;
    PORT
      LAYER M3 ;
      RECT 2.907 20.369 2.925 20.423 ;
    END
  END r0_rd_out[63]
  PIN r0_rd_out[64]
    DIRECTION OUTPUT ;
    USE SIGNAL ;
    SHAPE ABUTMENT ;
    PORT
      LAYER M3 ;
      RECT 3.447 20.369 3.465 20.423 ;
    END
  END r0_rd_out[64]
  PIN r0_rd_out[65]
    DIRECTION OUTPUT ;
    USE SIGNAL ;
    SHAPE ABUTMENT ;
    PORT
      LAYER M3 ;
      RECT 3.987 20.369 4.005 20.423 ;
    END
  END r0_rd_out[65]
  PIN r0_rd_out[66]
    DIRECTION OUTPUT ;
    USE SIGNAL ;
    SHAPE ABUTMENT ;
    PORT
      LAYER M3 ;
      RECT 4.527 20.369 4.545 20.423 ;
    END
  END r0_rd_out[66]
  PIN r0_rd_out[67]
    DIRECTION OUTPUT ;
    USE SIGNAL ;
    SHAPE ABUTMENT ;
    PORT
      LAYER M3 ;
      RECT 5.067 20.369 5.085 20.423 ;
    END
  END r0_rd_out[67]
  PIN r0_rd_out[68]
    DIRECTION OUTPUT ;
    USE SIGNAL ;
    SHAPE ABUTMENT ;
    PORT
      LAYER M3 ;
      RECT 5.607 20.369 5.625 20.423 ;
    END
  END r0_rd_out[68]
  PIN r0_rd_out[69]
    DIRECTION OUTPUT ;
    USE SIGNAL ;
    SHAPE ABUTMENT ;
    PORT
      LAYER M3 ;
      RECT 6.147 20.369 6.165 20.423 ;
    END
  END r0_rd_out[69]
  PIN r0_rd_out[70]
    DIRECTION OUTPUT ;
    USE SIGNAL ;
    SHAPE ABUTMENT ;
    PORT
      LAYER M3 ;
      RECT 6.687 20.369 6.705 20.423 ;
    END
  END r0_rd_out[70]
  PIN r0_rd_out[71]
    DIRECTION OUTPUT ;
    USE SIGNAL ;
    SHAPE ABUTMENT ;
    PORT
      LAYER M3 ;
      RECT 7.227 20.369 7.245 20.423 ;
    END
  END r0_rd_out[71]
  PIN r0_rd_out[72]
    DIRECTION OUTPUT ;
    USE SIGNAL ;
    SHAPE ABUTMENT ;
    PORT
      LAYER M3 ;
      RECT 7.767 20.369 7.785 20.423 ;
    END
  END r0_rd_out[72]
  PIN r0_rd_out[73]
    DIRECTION OUTPUT ;
    USE SIGNAL ;
    SHAPE ABUTMENT ;
    PORT
      LAYER M3 ;
      RECT 8.307 20.369 8.325 20.423 ;
    END
  END r0_rd_out[73]
  PIN r0_rd_out[74]
    DIRECTION OUTPUT ;
    USE SIGNAL ;
    SHAPE ABUTMENT ;
    PORT
      LAYER M3 ;
      RECT 8.847 20.369 8.865 20.423 ;
    END
  END r0_rd_out[74]
  PIN r0_rd_out[75]
    DIRECTION OUTPUT ;
    USE SIGNAL ;
    SHAPE ABUTMENT ;
    PORT
      LAYER M3 ;
      RECT 9.387 20.369 9.405 20.423 ;
    END
  END r0_rd_out[75]
  PIN r0_rd_out[76]
    DIRECTION OUTPUT ;
    USE SIGNAL ;
    SHAPE ABUTMENT ;
    PORT
      LAYER M3 ;
      RECT 9.927 20.369 9.945 20.423 ;
    END
  END r0_rd_out[76]
  PIN r0_rd_out[77]
    DIRECTION OUTPUT ;
    USE SIGNAL ;
    SHAPE ABUTMENT ;
    PORT
      LAYER M3 ;
      RECT 10.467 20.369 10.485 20.423 ;
    END
  END r0_rd_out[77]
  PIN r0_rd_out[78]
    DIRECTION OUTPUT ;
    USE SIGNAL ;
    SHAPE ABUTMENT ;
    PORT
      LAYER M3 ;
      RECT 11.007 20.369 11.025 20.423 ;
    END
  END r0_rd_out[78]
  PIN r0_rd_out[79]
    DIRECTION OUTPUT ;
    USE SIGNAL ;
    SHAPE ABUTMENT ;
    PORT
      LAYER M3 ;
      RECT 11.547 20.369 11.565 20.423 ;
    END
  END r0_rd_out[79]
  PIN r0_rd_out[80]
    DIRECTION OUTPUT ;
    USE SIGNAL ;
    SHAPE ABUTMENT ;
    PORT
      LAYER M3 ;
      RECT 12.087 20.369 12.105 20.423 ;
    END
  END r0_rd_out[80]
  PIN r0_rd_out[81]
    DIRECTION OUTPUT ;
    USE SIGNAL ;
    SHAPE ABUTMENT ;
    PORT
      LAYER M3 ;
      RECT 12.627 20.369 12.645 20.423 ;
    END
  END r0_rd_out[81]
  PIN r0_rd_out[82]
    DIRECTION OUTPUT ;
    USE SIGNAL ;
    SHAPE ABUTMENT ;
    PORT
      LAYER M3 ;
      RECT 13.167 20.369 13.185 20.423 ;
    END
  END r0_rd_out[82]
  PIN r0_rd_out[83]
    DIRECTION OUTPUT ;
    USE SIGNAL ;
    SHAPE ABUTMENT ;
    PORT
      LAYER M3 ;
      RECT 13.707 20.369 13.725 20.423 ;
    END
  END r0_rd_out[83]
  PIN r0_rd_out[84]
    DIRECTION OUTPUT ;
    USE SIGNAL ;
    SHAPE ABUTMENT ;
    PORT
      LAYER M3 ;
      RECT 14.247 20.369 14.265 20.423 ;
    END
  END r0_rd_out[84]
  PIN r0_rd_out[85]
    DIRECTION OUTPUT ;
    USE SIGNAL ;
    SHAPE ABUTMENT ;
    PORT
      LAYER M3 ;
      RECT 14.787 20.369 14.805 20.423 ;
    END
  END r0_rd_out[85]
  PIN r0_rd_out[86]
    DIRECTION OUTPUT ;
    USE SIGNAL ;
    SHAPE ABUTMENT ;
    PORT
      LAYER M3 ;
      RECT 15.327 20.369 15.345 20.423 ;
    END
  END r0_rd_out[86]
  PIN r0_rd_out[87]
    DIRECTION OUTPUT ;
    USE SIGNAL ;
    SHAPE ABUTMENT ;
    PORT
      LAYER M3 ;
      RECT 15.867 20.369 15.885 20.423 ;
    END
  END r0_rd_out[87]
  PIN r0_rd_out[88]
    DIRECTION OUTPUT ;
    USE SIGNAL ;
    SHAPE ABUTMENT ;
    PORT
      LAYER M3 ;
      RECT 16.407 20.369 16.425 20.423 ;
    END
  END r0_rd_out[88]
  PIN r0_rd_out[89]
    DIRECTION OUTPUT ;
    USE SIGNAL ;
    SHAPE ABUTMENT ;
    PORT
      LAYER M3 ;
      RECT 16.947 20.369 16.965 20.423 ;
    END
  END r0_rd_out[89]
  PIN r0_rd_out[90]
    DIRECTION OUTPUT ;
    USE SIGNAL ;
    SHAPE ABUTMENT ;
    PORT
      LAYER M3 ;
      RECT 17.487 20.369 17.505 20.423 ;
    END
  END r0_rd_out[90]
  PIN r0_rd_out[91]
    DIRECTION OUTPUT ;
    USE SIGNAL ;
    SHAPE ABUTMENT ;
    PORT
      LAYER M3 ;
      RECT 18.027 20.369 18.045 20.423 ;
    END
  END r0_rd_out[91]
  PIN r0_rd_out[92]
    DIRECTION OUTPUT ;
    USE SIGNAL ;
    SHAPE ABUTMENT ;
    PORT
      LAYER M3 ;
      RECT 18.567 20.369 18.585 20.423 ;
    END
  END r0_rd_out[92]
  PIN r0_rd_out[93]
    DIRECTION OUTPUT ;
    USE SIGNAL ;
    SHAPE ABUTMENT ;
    PORT
      LAYER M3 ;
      RECT 19.107 20.369 19.125 20.423 ;
    END
  END r0_rd_out[93]
  PIN r0_rd_out[94]
    DIRECTION OUTPUT ;
    USE SIGNAL ;
    SHAPE ABUTMENT ;
    PORT
      LAYER M3 ;
      RECT 19.647 20.369 19.665 20.423 ;
    END
  END r0_rd_out[94]
  PIN r0_rd_out[95]
    DIRECTION OUTPUT ;
    USE SIGNAL ;
    SHAPE ABUTMENT ;
    PORT
      LAYER M3 ;
      RECT 20.187 20.369 20.205 20.423 ;
    END
  END r0_rd_out[95]
  PIN r0_rd_out[96]
    DIRECTION OUTPUT ;
    USE SIGNAL ;
    SHAPE ABUTMENT ;
    PORT
      LAYER M3 ;
      RECT 20.727 20.369 20.745 20.423 ;
    END
  END r0_rd_out[96]
  PIN r0_rd_out[97]
    DIRECTION OUTPUT ;
    USE SIGNAL ;
    SHAPE ABUTMENT ;
    PORT
      LAYER M3 ;
      RECT 21.267 20.369 21.285 20.423 ;
    END
  END r0_rd_out[97]
  PIN r0_rd_out[98]
    DIRECTION OUTPUT ;
    USE SIGNAL ;
    SHAPE ABUTMENT ;
    PORT
      LAYER M3 ;
      RECT 21.807 20.369 21.825 20.423 ;
    END
  END r0_rd_out[98]
  PIN r0_rd_out[99]
    DIRECTION OUTPUT ;
    USE SIGNAL ;
    SHAPE ABUTMENT ;
    PORT
      LAYER M3 ;
      RECT 22.347 20.369 22.365 20.423 ;
    END
  END r0_rd_out[99]
  PIN r0_rd_out[100]
    DIRECTION OUTPUT ;
    USE SIGNAL ;
    SHAPE ABUTMENT ;
    PORT
      LAYER M3 ;
      RECT 22.887 20.369 22.905 20.423 ;
    END
  END r0_rd_out[100]
  PIN r0_rd_out[101]
    DIRECTION OUTPUT ;
    USE SIGNAL ;
    SHAPE ABUTMENT ;
    PORT
      LAYER M3 ;
      RECT 23.427 20.369 23.445 20.423 ;
    END
  END r0_rd_out[101]
  PIN r0_rd_out[102]
    DIRECTION OUTPUT ;
    USE SIGNAL ;
    SHAPE ABUTMENT ;
    PORT
      LAYER M3 ;
      RECT 23.967 20.369 23.985 20.423 ;
    END
  END r0_rd_out[102]
  PIN r0_rd_out[103]
    DIRECTION OUTPUT ;
    USE SIGNAL ;
    SHAPE ABUTMENT ;
    PORT
      LAYER M3 ;
      RECT 24.507 20.369 24.525 20.423 ;
    END
  END r0_rd_out[103]
  PIN r0_rd_out[104]
    DIRECTION OUTPUT ;
    USE SIGNAL ;
    SHAPE ABUTMENT ;
    PORT
      LAYER M3 ;
      RECT 25.047 20.369 25.065 20.423 ;
    END
  END r0_rd_out[104]
  PIN r0_rd_out[105]
    DIRECTION OUTPUT ;
    USE SIGNAL ;
    SHAPE ABUTMENT ;
    PORT
      LAYER M3 ;
      RECT 25.587 20.369 25.605 20.423 ;
    END
  END r0_rd_out[105]
  PIN r0_rd_out[106]
    DIRECTION OUTPUT ;
    USE SIGNAL ;
    SHAPE ABUTMENT ;
    PORT
      LAYER M3 ;
      RECT 26.127 20.369 26.145 20.423 ;
    END
  END r0_rd_out[106]
  PIN r0_rd_out[107]
    DIRECTION OUTPUT ;
    USE SIGNAL ;
    SHAPE ABUTMENT ;
    PORT
      LAYER M3 ;
      RECT 26.667 20.369 26.685 20.423 ;
    END
  END r0_rd_out[107]
  PIN r0_rd_out[108]
    DIRECTION OUTPUT ;
    USE SIGNAL ;
    SHAPE ABUTMENT ;
    PORT
      LAYER M3 ;
      RECT 27.207 20.369 27.225 20.423 ;
    END
  END r0_rd_out[108]
  PIN r0_rd_out[109]
    DIRECTION OUTPUT ;
    USE SIGNAL ;
    SHAPE ABUTMENT ;
    PORT
      LAYER M3 ;
      RECT 27.747 20.369 27.765 20.423 ;
    END
  END r0_rd_out[109]
  PIN r0_rd_out[110]
    DIRECTION OUTPUT ;
    USE SIGNAL ;
    SHAPE ABUTMENT ;
    PORT
      LAYER M3 ;
      RECT 28.287 20.369 28.305 20.423 ;
    END
  END r0_rd_out[110]
  PIN r0_rd_out[111]
    DIRECTION OUTPUT ;
    USE SIGNAL ;
    SHAPE ABUTMENT ;
    PORT
      LAYER M3 ;
      RECT 28.827 20.369 28.845 20.423 ;
    END
  END r0_rd_out[111]
  PIN r0_rd_out[112]
    DIRECTION OUTPUT ;
    USE SIGNAL ;
    SHAPE ABUTMENT ;
    PORT
      LAYER M3 ;
      RECT 29.367 20.369 29.385 20.423 ;
    END
  END r0_rd_out[112]
  PIN r0_rd_out[113]
    DIRECTION OUTPUT ;
    USE SIGNAL ;
    SHAPE ABUTMENT ;
    PORT
      LAYER M3 ;
      RECT 29.907 20.369 29.925 20.423 ;
    END
  END r0_rd_out[113]
  PIN r0_rd_out[114]
    DIRECTION OUTPUT ;
    USE SIGNAL ;
    SHAPE ABUTMENT ;
    PORT
      LAYER M3 ;
      RECT 30.447 20.369 30.465 20.423 ;
    END
  END r0_rd_out[114]
  PIN r0_rd_out[115]
    DIRECTION OUTPUT ;
    USE SIGNAL ;
    SHAPE ABUTMENT ;
    PORT
      LAYER M3 ;
      RECT 30.987 20.369 31.005 20.423 ;
    END
  END r0_rd_out[115]
  PIN w0_addr_in[0]
    DIRECTION INPUT ;
    USE SIGNAL ;
    SHAPE ABUTMENT ;
    PORT
      LAYER M4 ;
      RECT 0.000 15.588 0.072 15.612 ;
    END
  END w0_addr_in[0]
  PIN w0_addr_in[1]
    DIRECTION INPUT ;
    USE SIGNAL ;
    SHAPE ABUTMENT ;
    PORT
      LAYER M4 ;
      RECT 0.000 16.116 0.072 16.140 ;
    END
  END w0_addr_in[1]
  PIN w0_addr_in[2]
    DIRECTION INPUT ;
    USE SIGNAL ;
    SHAPE ABUTMENT ;
    PORT
      LAYER M4 ;
      RECT 0.000 16.644 0.072 16.668 ;
    END
  END w0_addr_in[2]
  PIN w0_addr_in[3]
    DIRECTION INPUT ;
    USE SIGNAL ;
    SHAPE ABUTMENT ;
    PORT
      LAYER M4 ;
      RECT 34.882 15.588 34.954 15.612 ;
    END
  END w0_addr_in[3]
  PIN w0_addr_in[4]
    DIRECTION INPUT ;
    USE SIGNAL ;
    SHAPE ABUTMENT ;
    PORT
      LAYER M4 ;
      RECT 34.882 16.116 34.954 16.140 ;
    END
  END w0_addr_in[4]
  PIN w0_addr_in[5]
    DIRECTION INPUT ;
    USE SIGNAL ;
    SHAPE ABUTMENT ;
    PORT
      LAYER M4 ;
      RECT 34.882 16.644 34.954 16.668 ;
    END
  END w0_addr_in[5]
  PIN r0_addr_in[0]
    DIRECTION INPUT ;
    USE SIGNAL ;
    SHAPE ABUTMENT ;
    PORT
      LAYER M4 ;
      RECT 0.000 17.172 0.072 17.196 ;
    END
  END r0_addr_in[0]
  PIN r0_addr_in[1]
    DIRECTION INPUT ;
    USE SIGNAL ;
    SHAPE ABUTMENT ;
    PORT
      LAYER M4 ;
      RECT 0.000 17.700 0.072 17.724 ;
    END
  END r0_addr_in[1]
  PIN r0_addr_in[2]
    DIRECTION INPUT ;
    USE SIGNAL ;
    SHAPE ABUTMENT ;
    PORT
      LAYER M4 ;
      RECT 0.000 18.228 0.072 18.252 ;
    END
  END r0_addr_in[2]
  PIN r0_addr_in[3]
    DIRECTION INPUT ;
    USE SIGNAL ;
    SHAPE ABUTMENT ;
    PORT
      LAYER M4 ;
      RECT 34.882 17.172 34.954 17.196 ;
    END
  END r0_addr_in[3]
  PIN r0_addr_in[4]
    DIRECTION INPUT ;
    USE SIGNAL ;
    SHAPE ABUTMENT ;
    PORT
      LAYER M4 ;
      RECT 34.882 17.700 34.954 17.724 ;
    END
  END r0_addr_in[4]
  PIN r0_addr_in[5]
    DIRECTION INPUT ;
    USE SIGNAL ;
    SHAPE ABUTMENT ;
    PORT
      LAYER M4 ;
      RECT 34.882 18.228 34.954 18.252 ;
    END
  END r0_addr_in[5]
  PIN w0_we_in
    DIRECTION INPUT ;
    USE SIGNAL ;
    SHAPE ABUTMENT ;
    PORT
      LAYER M3 ;
      RECT 31.527 20.369 31.545 20.423 ;
    END
  END w0_we_in
  PIN w0_ce_in
    DIRECTION INPUT ;
    USE SIGNAL ;
    SHAPE ABUTMENT ;
    PORT
      LAYER M3 ;
      RECT 32.067 20.369 32.085 20.423 ;
    END
  END w0_ce_in
  PIN w0_clk
    DIRECTION INPUT ;
    USE SIGNAL ;
    SHAPE ABUTMENT ;
    PORT
      LAYER M3 ;
      RECT 32.607 20.369 32.625 20.423 ;
    END
  END w0_clk
  PIN r0_ce_in
    DIRECTION INPUT ;
    USE SIGNAL ;
    SHAPE ABUTMENT ;
    PORT
      LAYER M3 ;
      RECT 33.147 20.369 33.165 20.423 ;
    END
  END r0_ce_in
  PIN r0_clk
    DIRECTION INPUT ;
    USE SIGNAL ;
    SHAPE ABUTMENT ;
    PORT
      LAYER M3 ;
      RECT 33.687 20.369 33.705 20.423 ;
    END
  END r0_clk
  PIN VSS
    DIRECTION INOUT ;
    USE GROUND ;
    PORT
      LAYER M4 ;
      RECT 0.216 0.240 34.738 0.336 ;
      RECT 0.216 1.008 34.738 1.104 ;
      RECT 0.216 1.776 34.738 1.872 ;
      RECT 0.216 2.544 34.738 2.640 ;
      RECT 0.216 3.312 34.738 3.408 ;
      RECT 0.216 4.080 34.738 4.176 ;
      RECT 0.216 4.848 34.738 4.944 ;
      RECT 0.216 5.616 34.738 5.712 ;
      RECT 0.216 6.384 34.738 6.480 ;
      RECT 0.216 7.152 34.738 7.248 ;
      RECT 0.216 7.920 34.738 8.016 ;
      RECT 0.216 8.688 34.738 8.784 ;
      RECT 0.216 9.456 34.738 9.552 ;
      RECT 0.216 10.224 34.738 10.320 ;
      RECT 0.216 10.992 34.738 11.088 ;
      RECT 0.216 11.760 34.738 11.856 ;
      RECT 0.216 12.528 34.738 12.624 ;
      RECT 0.216 13.296 34.738 13.392 ;
      RECT 0.216 14.064 34.738 14.160 ;
      RECT 0.216 14.832 34.738 14.928 ;
      RECT 0.216 15.600 34.738 15.696 ;
      RECT 0.216 16.368 34.738 16.464 ;
      RECT 0.216 17.136 34.738 17.232 ;
      RECT 0.216 17.904 34.738 18.000 ;
      RECT 0.216 18.672 34.738 18.768 ;
      RECT 0.216 19.440 34.738 19.536 ;
      RECT 0.216 20.208 34.738 20.304 ;
    END
  END VSS
  PIN VDD
    DIRECTION INOUT ;
    USE POWER ;
    PORT
      LAYER M4 ;
      RECT 0.216 0.240 34.738 0.336 ;
      RECT 0.216 1.008 34.738 1.104 ;
      RECT 0.216 1.776 34.738 1.872 ;
      RECT 0.216 2.544 34.738 2.640 ;
      RECT 0.216 3.312 34.738 3.408 ;
      RECT 0.216 4.080 34.738 4.176 ;
      RECT 0.216 4.848 34.738 4.944 ;
      RECT 0.216 5.616 34.738 5.712 ;
      RECT 0.216 6.384 34.738 6.480 ;
      RECT 0.216 7.152 34.738 7.248 ;
      RECT 0.216 7.920 34.738 8.016 ;
      RECT 0.216 8.688 34.738 8.784 ;
      RECT 0.216 9.456 34.738 9.552 ;
      RECT 0.216 10.224 34.738 10.320 ;
      RECT 0.216 10.992 34.738 11.088 ;
      RECT 0.216 11.760 34.738 11.856 ;
      RECT 0.216 12.528 34.738 12.624 ;
      RECT 0.216 13.296 34.738 13.392 ;
      RECT 0.216 14.064 34.738 14.160 ;
      RECT 0.216 14.832 34.738 14.928 ;
      RECT 0.216 15.600 34.738 15.696 ;
      RECT 0.216 16.368 34.738 16.464 ;
      RECT 0.216 17.136 34.738 17.232 ;
      RECT 0.216 17.904 34.738 18.000 ;
      RECT 0.216 18.672 34.738 18.768 ;
      RECT 0.216 19.440 34.738 19.536 ;
      RECT 0.216 20.208 34.738 20.304 ;
    END
  END VDD
  OBS
    LAYER M1 ;
    RECT 0 0 34.954 20.423 ;
    LAYER M2 ;
    RECT 0 0 34.954 20.423 ;
    LAYER M3 ;
    RECT 0 0 34.954 20.423 ;
    LAYER M4 ;
    RECT 0 0 34.954 20.423 ;
  END
END fakeram_116x64_1r1w

END LIBRARY
